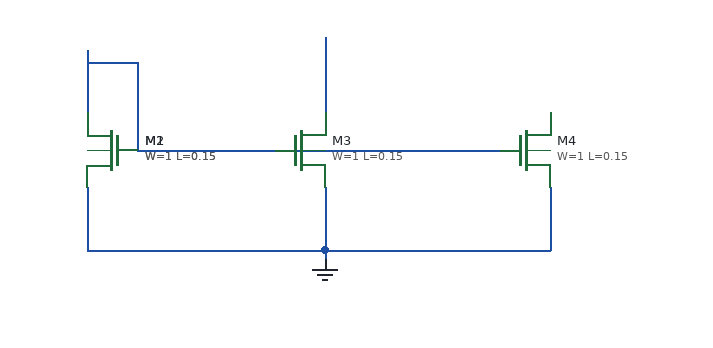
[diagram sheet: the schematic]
v {xschem version=3.1.0 file_version=1.2
}
G {}
K {}
V {}
S {}
E {}
N -10 -70 -10 -20 {
lab=#net1}
N 30 -60 30 10 {
lab=#net1}
N -10 -60 30 -60 {
lab=#net1}
N 30 10 140 10 {
lab=#net1}
N 140 10 320 10 {
lab=#net1}
N 180 -80 180 -20 {
lab=#net2}
N -10 40 -10 90 {
lab=#net3}
N -10 90 180 90 {
lab=#net3}
N 180 40 180 90 {
lab=#net3}
N 360 40 360 90 {
lab=#net3}
N 180 90 360 90 {
lab=#net3}
N 180.3125 99.0625 180.3125 100.3125 {
lab=GND}
N 180 90.3125 180 99.375 {}
C {sky130_fd_pr/nfet_01v8_lvt.sym} 10 10 0 1 {name=M1
L=0.15
W=1
nf=1
mult=1
ad="'int((nf+1)/2) * W/nf * 0.29'" 
pd="'2*int((nf+1)/2) * (W/nf + 0.29)'"
as="'int((nf+2)/2) * W/nf * 0.29'" 
ps="'2*int((nf+2)/2) * (W/nf + 0.29)'"
nrd="'0.29 / W'" nrs="'0.29 / W'"
sa=0 sb=0 sd=0
model=nfet_01v8_lvt
spiceprefix=X
}
C {sky130_fd_pr/nfet_01v8_lvt.sym} 10 10 0 1 {name=M2
L=0.15
W=1
nf=1
mult=1
ad="'int((nf+1)/2) * W/nf * 0.29'" 
pd="'2*int((nf+1)/2) * (W/nf + 0.29)'"
as="'int((nf+2)/2) * W/nf * 0.29'" 
ps="'2*int((nf+2)/2) * (W/nf + 0.29)'"
nrd="'0.29 / W'" nrs="'0.29 / W'"
sa=0 sb=0 sd=0
model=nfet_01v8_lvt
spiceprefix=X
}
C {sky130_fd_pr/nfet_01v8_lvt.sym} 160 10 0 0 {name=M3
L=0.15
W=1
nf=1
mult=1
ad="'int((nf+1)/2) * W/nf * 0.29'" 
pd="'2*int((nf+1)/2) * (W/nf + 0.29)'"
as="'int((nf+2)/2) * W/nf * 0.29'" 
ps="'2*int((nf+2)/2) * (W/nf + 0.29)'"
nrd="'0.29 / W'" nrs="'0.29 / W'"
sa=0 sb=0 sd=0
model=nfet_01v8_lvt
spiceprefix=X
}
C {sky130_fd_pr/nfet_01v8_lvt.sym} 340 10 0 0 {name=M4
L=0.15
W=1
nf=1
mult=1
ad="'int((nf+1)/2) * W/nf * 0.29'" 
pd="'2*int((nf+1)/2) * (W/nf + 0.29)'"
as="'int((nf+2)/2) * W/nf * 0.29'" 
ps="'2*int((nf+2)/2) * (W/nf + 0.29)'"
nrd="'0.29 / W'" nrs="'0.29 / W'"
sa=0 sb=0 sd=0
model=nfet_01v8_lvt
spiceprefix=X
}
C {devices/gnd.sym} 180.3125 97.8125 0 0 {name=l1 lab=GND}
